VERSION 5.7 ;
  NOWIREEXTENSIONATPIN ON ;
  DIVIDERCHAR "/" ;
  BUSBITCHARS "[]" ;
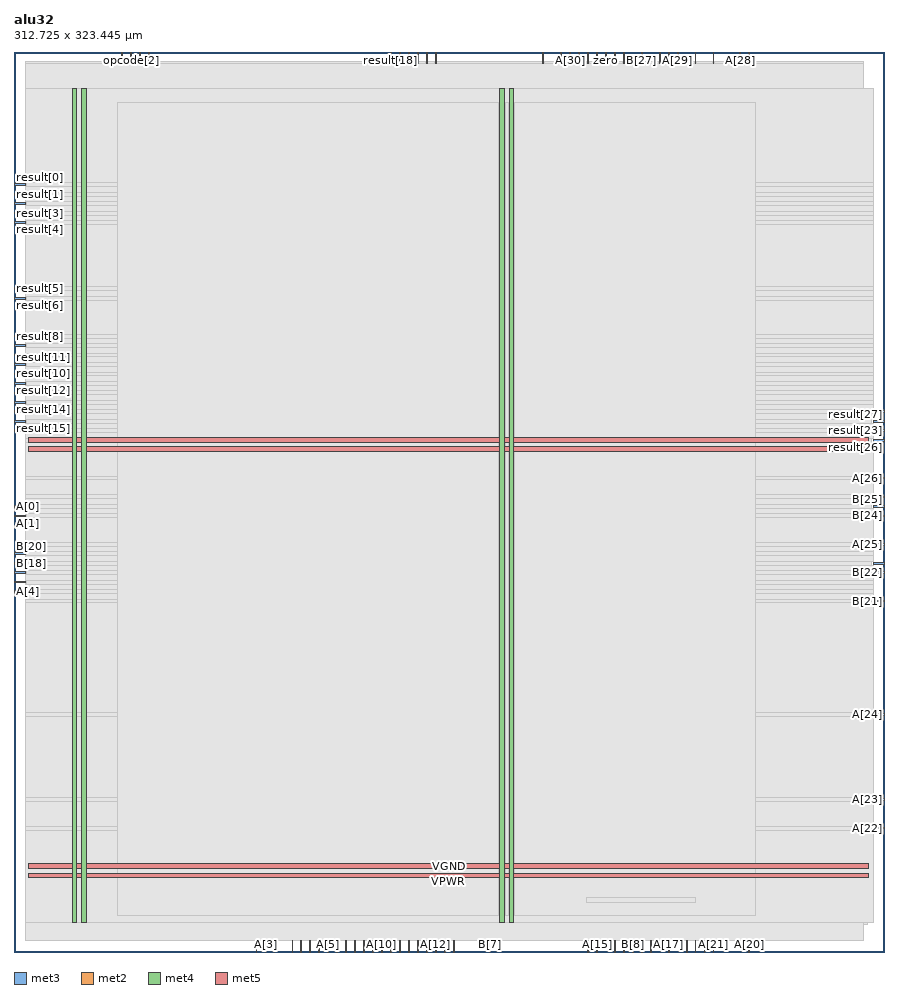
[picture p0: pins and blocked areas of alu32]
MACRO alu32
  CLASS BLOCK ;
  FOREIGN alu32 ;
  ORIGIN 0.000 0.000 ;
  SIZE 312.725 BY 323.445 ;
  PIN A[0]
    DIRECTION INPUT ;
    USE SIGNAL ;
    ANTENNAGATEAREA 0.196500 ;
    PORT
      LAYER met3 ;
        RECT 0.000 159.840 4.000 160.440 ;
    END
  END A[0]
  PIN A[10]
    DIRECTION INPUT ;
    USE SIGNAL ;
    ANTENNAGATEAREA 0.196500 ;
    PORT
      LAYER met2 ;
        RECT 132.110 0.000 132.390 4.000 ;
    END
  END A[10]
  PIN A[11]
    DIRECTION INPUT ;
    USE SIGNAL ;
    ANTENNAGATEAREA 0.372000 ;
    PORT
      LAYER met2 ;
        RECT 125.670 0.000 125.950 4.000 ;
    END
  END A[11]
  PIN A[12]
    DIRECTION INPUT ;
    USE SIGNAL ;
    ANTENNAGATEAREA 0.213000 ;
    PORT
      LAYER met2 ;
        RECT 151.430 0.000 151.710 4.000 ;
    END
  END A[12]
  PIN A[13]
    DIRECTION INPUT ;
    USE SIGNAL ;
    ANTENNAGATEAREA 0.213000 ;
    PORT
      LAYER met2 ;
        RECT 138.550 0.000 138.830 4.000 ;
    END
  END A[13]
  PIN A[14]
    DIRECTION INPUT ;
    USE SIGNAL ;
    ANTENNAGATEAREA 0.159000 ;
    PORT
      LAYER met2 ;
        RECT 144.990 0.000 145.270 4.000 ;
    END
  END A[14]
  PIN A[15]
    DIRECTION INPUT ;
    USE SIGNAL ;
    ANTENNAGATEAREA 0.213000 ;
    PORT
      LAYER met2 ;
        RECT 209.390 0.000 209.670 4.000 ;
    END
  END A[15]
  PIN A[16]
    DIRECTION INPUT ;
    USE SIGNAL ;
    ANTENNAGATEAREA 0.247500 ;
    PORT
      LAYER met2 ;
        RECT 215.830 0.000 216.110 4.000 ;
    END
  END A[16]
  PIN A[17]
    DIRECTION INPUT ;
    USE SIGNAL ;
    ANTENNAGATEAREA 0.495000 ;
    PORT
      LAYER met2 ;
        RECT 235.150 0.000 235.430 4.000 ;
    END
  END A[17]
  PIN A[18]
    DIRECTION INPUT ;
    USE SIGNAL ;
    ANTENNAGATEAREA 0.213000 ;
    PORT
      LAYER met2 ;
        RECT 206.170 0.000 206.450 4.000 ;
    END
  END A[18]
  PIN A[19]
    DIRECTION INPUT ;
    USE SIGNAL ;
    ANTENNAGATEAREA 0.159000 ;
    PORT
      LAYER met2 ;
        RECT 225.490 0.000 225.770 4.000 ;
    END
  END A[19]
  PIN A[1]
    DIRECTION INPUT ;
    USE SIGNAL ;
    ANTENNAGATEAREA 0.213000 ;
    PORT
      LAYER met3 ;
        RECT 0.000 156.440 4.000 157.040 ;
    END
  END A[1]
  PIN A[20]
    DIRECTION INPUT ;
    USE SIGNAL ;
    ANTENNAGATEAREA 0.196500 ;
    PORT
      LAYER met2 ;
        RECT 264.130 0.000 264.410 4.000 ;
    END
  END A[20]
  PIN A[21]
    DIRECTION INPUT ;
    USE SIGNAL ;
    ANTENNAGATEAREA 0.196500 ;
    PORT
      LAYER met2 ;
        RECT 251.250 0.000 251.530 4.000 ;
    END
  END A[21]
  PIN A[22]
    DIRECTION INPUT ;
    USE SIGNAL ;
    ANTENNAGATEAREA 0.213000 ;
    PORT
      LAYER met3 ;
        RECT 308.725 44.240 312.725 44.840 ;
    END
  END A[22]
  PIN A[23]
    DIRECTION INPUT ;
    USE SIGNAL ;
    ANTENNAGATEAREA 0.159000 ;
    PORT
      LAYER met3 ;
        RECT 308.725 54.440 312.725 55.040 ;
    END
  END A[23]
  PIN A[24]
    DIRECTION INPUT ;
    USE SIGNAL ;
    ANTENNAGATEAREA 0.159000 ;
    PORT
      LAYER met3 ;
        RECT 308.725 85.040 312.725 85.640 ;
    END
  END A[24]
  PIN A[25]
    DIRECTION INPUT ;
    USE SIGNAL ;
    ANTENNAGATEAREA 0.196500 ;
    PORT
      LAYER met3 ;
        RECT 308.725 146.240 312.725 146.840 ;
    END
  END A[25]
  PIN A[26]
    DIRECTION INPUT ;
    USE SIGNAL ;
    ANTENNAGATEAREA 0.213000 ;
    PORT
      LAYER met3 ;
        RECT 308.725 170.040 312.725 170.640 ;
    END
  END A[26]
  PIN A[27]
    DIRECTION INPUT ;
    USE SIGNAL ;
    ANTENNAGATEAREA 0.159000 ;
    PORT
      LAYER met2 ;
        RECT 264.130 319.445 264.410 323.445 ;
    END
  END A[27]
  PIN A[28]
    DIRECTION INPUT ;
    USE SIGNAL ;
    ANTENNAGATEAREA 0.213000 ;
    PORT
      LAYER met2 ;
        RECT 260.910 319.445 261.190 323.445 ;
    END
  END A[28]
  PIN A[29]
    DIRECTION INPUT ;
    USE SIGNAL ;
    ANTENNAGATEAREA 0.196500 ;
    PORT
      LAYER met2 ;
        RECT 238.370 319.445 238.650 323.445 ;
    END
  END A[29]
  PIN A[2]
    DIRECTION INPUT ;
    USE SIGNAL ;
    ANTENNAGATEAREA 0.196500 ;
    PORT
      LAYER met3 ;
        RECT 0.000 132.640 4.000 133.240 ;
    END
  END A[2]
  PIN A[30]
    DIRECTION INPUT ;
    USE SIGNAL ;
    ANTENNAGATEAREA 0.213000 ;
    PORT
      LAYER met2 ;
        RECT 199.730 319.445 200.010 323.445 ;
    END
  END A[30]
  PIN A[31]
    DIRECTION INPUT ;
    USE SIGNAL ;
    ANTENNAGATEAREA 0.159000 ;
    PORT
      LAYER met2 ;
        RECT 196.510 319.445 196.790 323.445 ;
    END
  END A[31]
  PIN A[3]
    DIRECTION INPUT ;
    USE SIGNAL ;
    ANTENNAGATEAREA 0.159000 ;
    PORT
      LAYER met2 ;
        RECT 90.250 0.000 90.530 4.000 ;
    END
  END A[3]
  PIN A[4]
    DIRECTION INPUT ;
    USE SIGNAL ;
    ANTENNAGATEAREA 0.213000 ;
    PORT
      LAYER met3 ;
        RECT 0.000 129.240 4.000 129.840 ;
    END
  END A[4]
  PIN A[5]
    DIRECTION INPUT ;
    USE SIGNAL ;
    ANTENNAGATEAREA 0.213000 ;
    PORT
      LAYER met2 ;
        RECT 112.790 0.000 113.070 4.000 ;
    END
  END A[5]
  PIN A[6]
    DIRECTION INPUT ;
    USE SIGNAL ;
    ANTENNAGATEAREA 0.159000 ;
    PORT
      LAYER met2 ;
        RECT 93.470 0.000 93.750 4.000 ;
    END
  END A[6]
  PIN A[7]
    DIRECTION INPUT ;
    USE SIGNAL ;
    ANTENNAGATEAREA 0.159000 ;
    PORT
      LAYER met2 ;
        RECT 87.030 0.000 87.310 4.000 ;
    END
  END A[7]
  PIN A[8]
    DIRECTION INPUT ;
    USE SIGNAL ;
    ANTENNAGATEAREA 0.213000 ;
    PORT
      LAYER met2 ;
        RECT 99.910 0.000 100.190 4.000 ;
    END
  END A[8]
  PIN A[9]
    DIRECTION INPUT ;
    USE SIGNAL ;
    ANTENNAGATEAREA 0.159000 ;
    PORT
      LAYER met2 ;
        RECT 128.890 0.000 129.170 4.000 ;
    END
  END A[9]
  PIN B[0]
    DIRECTION INPUT ;
    USE SIGNAL ;
    ANTENNAGATEAREA 0.213000 ;
    PORT
      LAYER met2 ;
        RECT 244.810 0.000 245.090 4.000 ;
    END
  END B[0]
  PIN B[10]
    DIRECTION INPUT ;
    USE SIGNAL ;
    ANTENNAGATEAREA 0.318000 ;
    PORT
      LAYER met2 ;
        RECT 148.210 0.000 148.490 4.000 ;
    END
  END B[10]
  PIN B[11]
    DIRECTION INPUT ;
    USE SIGNAL ;
    ANTENNAGATEAREA 0.196500 ;
    PORT
      LAYER met2 ;
        RECT 106.350 0.000 106.630 4.000 ;
    END
  END B[11]
  PIN B[12]
    DIRECTION INPUT ;
    USE SIGNAL ;
    ANTENNAGATEAREA 0.159000 ;
    PORT
      LAYER met2 ;
        RECT 135.330 0.000 135.610 4.000 ;
    END
  END B[12]
  PIN B[13]
    DIRECTION INPUT ;
    USE SIGNAL ;
    ANTENNAGATEAREA 0.196500 ;
    PORT
      LAYER met2 ;
        RECT 109.570 0.000 109.850 4.000 ;
    END
  END B[13]
  PIN B[14]
    DIRECTION INPUT ;
    USE SIGNAL ;
    ANTENNAGATEAREA 0.159000 ;
    PORT
      LAYER met2 ;
        RECT 103.130 0.000 103.410 4.000 ;
    END
  END B[14]
  PIN B[15]
    DIRECTION INPUT ;
    USE SIGNAL ;
    ANTENNAGATEAREA 0.159000 ;
    PORT
      LAYER met2 ;
        RECT 119.230 0.000 119.510 4.000 ;
    END
  END B[15]
  PIN B[16]
    DIRECTION INPUT ;
    USE SIGNAL ;
    ANTENNAGATEAREA 0.159000 ;
    PORT
      LAYER met2 ;
        RECT 116.010 0.000 116.290 4.000 ;
    END
  END B[16]
  PIN B[17]
    DIRECTION INPUT ;
    USE SIGNAL ;
    ANTENNAGATEAREA 0.196500 ;
    PORT
      LAYER met2 ;
        RECT 122.450 0.000 122.730 4.000 ;
    END
  END B[17]
  PIN B[18]
    DIRECTION INPUT ;
    USE SIGNAL ;
    ANTENNAGATEAREA 0.213000 ;
    PORT
      LAYER met3 ;
        RECT 0.000 139.440 4.000 140.040 ;
    END
  END B[18]
  PIN B[19]
    DIRECTION INPUT ;
    USE SIGNAL ;
    ANTENNAGATEAREA 0.213000 ;
    PORT
      LAYER met3 ;
        RECT 0.000 136.040 4.000 136.640 ;
    END
  END B[19]
  PIN B[1]
    DIRECTION INPUT ;
    USE SIGNAL ;
    ANTENNAGATEAREA 0.213000 ;
    PORT
      LAYER met2 ;
        RECT 241.590 0.000 241.870 4.000 ;
    END
  END B[1]
  PIN B[20]
    DIRECTION INPUT ;
    USE SIGNAL ;
    ANTENNAGATEAREA 0.126000 ;
    PORT
      LAYER met3 ;
        RECT 0.000 142.840 4.000 143.440 ;
    END
  END B[20]
  PIN B[21]
    DIRECTION INPUT ;
    USE SIGNAL ;
    ANTENNAGATEAREA 0.159000 ;
    PORT
      LAYER met3 ;
        RECT 308.725 125.840 312.725 126.440 ;
    END
  END B[21]
  PIN B[22]
    DIRECTION INPUT ;
    USE SIGNAL ;
    ANTENNAGATEAREA 0.213000 ;
    PORT
      LAYER met3 ;
        RECT 308.725 136.040 312.725 136.640 ;
    END
  END B[22]
  PIN B[23]
    DIRECTION INPUT ;
    USE SIGNAL ;
    ANTENNAGATEAREA 0.213000 ;
    PORT
      LAYER met3 ;
        RECT 308.725 139.440 312.725 140.040 ;
    END
  END B[23]
  PIN B[24]
    DIRECTION INPUT ;
    USE SIGNAL ;
    ANTENNAGATEAREA 0.159000 ;
    PORT
      LAYER met3 ;
        RECT 308.725 156.440 312.725 157.040 ;
    END
  END B[24]
  PIN B[25]
    DIRECTION INPUT ;
    USE SIGNAL ;
    ANTENNAGATEAREA 0.159000 ;
    PORT
      LAYER met3 ;
        RECT 308.725 159.840 312.725 160.440 ;
    END
  END B[25]
  PIN B[26]
    DIRECTION INPUT ;
    USE SIGNAL ;
    ANTENNAGATEAREA 0.196500 ;
    PORT
      LAYER met3 ;
        RECT 308.725 163.240 312.725 163.840 ;
    END
  END B[26]
  PIN B[27]
    DIRECTION INPUT ;
    USE SIGNAL ;
    ANTENNAGATEAREA 0.213000 ;
    PORT
      LAYER met2 ;
        RECT 225.490 319.445 225.770 323.445 ;
    END
  END B[27]
  PIN B[28]
    DIRECTION INPUT ;
    USE SIGNAL ;
    ANTENNAGATEAREA 0.213000 ;
    PORT
      LAYER met2 ;
        RECT 251.250 319.445 251.530 323.445 ;
    END
  END B[28]
  PIN B[29]
    DIRECTION INPUT ;
    USE SIGNAL ;
    ANTENNAGATEAREA 0.196500 ;
    PORT
      LAYER met2 ;
        RECT 235.150 319.445 235.430 323.445 ;
    END
  END B[29]
  PIN B[2]
    DIRECTION INPUT ;
    USE SIGNAL ;
    ANTENNAGATEAREA 1.842000 ;
    PORT
      LAYER met2 ;
        RECT 154.650 0.000 154.930 4.000 ;
    END
  END B[2]
  PIN B[30]
    DIRECTION INPUT ;
    USE SIGNAL ;
    ANTENNAGATEAREA 0.159000 ;
    PORT
      LAYER met2 ;
        RECT 244.810 319.445 245.090 323.445 ;
    END
  END B[30]
  PIN B[31]
    DIRECTION INPUT ;
    USE SIGNAL ;
    ANTENNAGATEAREA 0.126000 ;
    PORT
      LAYER met2 ;
        RECT 231.930 319.445 232.210 323.445 ;
    END
  END B[31]
  PIN B[3]
    DIRECTION INPUT ;
    USE SIGNAL ;
    ANTENNAGATEAREA 0.495000 ;
    PORT
      LAYER met2 ;
        RECT 219.050 0.000 219.330 4.000 ;
    END
  END B[3]
  PIN B[4]
    DIRECTION INPUT ;
    USE SIGNAL ;
    ANTENNAGATEAREA 0.213000 ;
    PORT
      LAYER met2 ;
        RECT 248.030 0.000 248.310 4.000 ;
    END
  END B[4]
  PIN B[5]
    DIRECTION INPUT ;
    USE SIGNAL ;
    ANTENNAGATEAREA 0.196500 ;
    PORT
      LAYER met2 ;
        RECT 228.710 0.000 228.990 4.000 ;
    END
  END B[5]
  PIN B[6]
    DIRECTION INPUT ;
    USE SIGNAL ;
    ANTENNAGATEAREA 0.159000 ;
    PORT
      LAYER met2 ;
        RECT 157.870 0.000 158.150 4.000 ;
    END
  END B[6]
  PIN B[7]
    DIRECTION INPUT ;
    USE SIGNAL ;
    ANTENNAGATEAREA 0.213000 ;
    PORT
      LAYER met2 ;
        RECT 170.750 0.000 171.030 4.000 ;
    END
  END B[7]
  PIN B[8]
    DIRECTION INPUT ;
    USE SIGNAL ;
    ANTENNAGATEAREA 0.196500 ;
    PORT
      LAYER met2 ;
        RECT 222.270 0.000 222.550 4.000 ;
    END
  END B[8]
  PIN B[9]
    DIRECTION INPUT ;
    USE SIGNAL ;
    ANTENNAGATEAREA 0.196500 ;
    PORT
      LAYER met2 ;
        RECT 141.770 0.000 142.050 4.000 ;
    END
  END B[9]
  PIN VGND
    DIRECTION INOUT ;
    USE GROUND ;
    PORT
      LAYER met4 ;
        RECT 24.340 10.640 25.940 310.320 ;
    END
    PORT
      LAYER met4 ;
        RECT 177.940 10.640 179.540 310.320 ;
    END
    PORT
      LAYER met5 ;
        RECT 5.280 30.030 307.060 31.630 ;
    END
    PORT
      LAYER met5 ;
        RECT 5.280 183.210 307.060 184.810 ;
    END
  END VGND
  PIN VPWR
    DIRECTION INOUT ;
    USE POWER ;
    PORT
      LAYER met4 ;
        RECT 21.040 10.640 22.640 310.320 ;
    END
    PORT
      LAYER met4 ;
        RECT 174.640 10.640 176.240 310.320 ;
    END
    PORT
      LAYER met5 ;
        RECT 5.280 26.730 307.060 28.330 ;
    END
    PORT
      LAYER met5 ;
        RECT 5.280 179.910 307.060 181.510 ;
    END
  END VPWR
  PIN carry
    DIRECTION OUTPUT ;
    USE SIGNAL ;
    ANTENNADIFFAREA 0.795200 ;
    PORT
      LAYER met2 ;
        RECT 209.390 319.445 209.670 323.445 ;
    END
  END carry
  PIN opcode[0]
    DIRECTION INPUT ;
    USE SIGNAL ;
    ANTENNAGATEAREA 0.159000 ;
    PORT
      LAYER met2 ;
        RECT 48.390 319.445 48.670 323.445 ;
    END
  END opcode[0]
  PIN opcode[1]
    DIRECTION INPUT ;
    USE SIGNAL ;
    ANTENNAGATEAREA 0.159000 ;
    PORT
      LAYER met2 ;
        RECT 38.730 319.445 39.010 323.445 ;
    END
  END opcode[1]
  PIN opcode[2]
    DIRECTION INPUT ;
    USE SIGNAL ;
    ANTENNAGATEAREA 0.213000 ;
    PORT
      LAYER met2 ;
        RECT 41.950 319.445 42.230 323.445 ;
    END
  END opcode[2]
  PIN opcode[3]
    DIRECTION INPUT ;
    USE SIGNAL ;
    ANTENNAGATEAREA 0.213000 ;
    PORT
      LAYER met2 ;
        RECT 45.170 319.445 45.450 323.445 ;
    END
  END opcode[3]
  PIN overflow
    DIRECTION OUTPUT ;
    USE SIGNAL ;
    ANTENNADIFFAREA 0.795200 ;
    PORT
      LAYER met2 ;
        RECT 219.050 319.445 219.330 323.445 ;
    END
  END overflow
  PIN result[0]
    DIRECTION OUTPUT ;
    USE SIGNAL ;
    ANTENNADIFFAREA 0.445500 ;
    PORT
      LAYER met3 ;
        RECT 0.000 275.440 4.000 276.040 ;
    END
  END result[0]
  PIN result[10]
    DIRECTION OUTPUT ;
    USE SIGNAL ;
    ANTENNADIFFAREA 0.445500 ;
    PORT
      LAYER met3 ;
        RECT 0.000 207.440 4.000 208.040 ;
    END
  END result[10]
  PIN result[11]
    DIRECTION OUTPUT ;
    USE SIGNAL ;
    ANTENNADIFFAREA 0.445500 ;
    PORT
      LAYER met3 ;
        RECT 0.000 210.840 4.000 211.440 ;
    END
  END result[11]
  PIN result[12]
    DIRECTION OUTPUT ;
    USE SIGNAL ;
    ANTENNADIFFAREA 0.445500 ;
    PORT
      LAYER met3 ;
        RECT 0.000 204.040 4.000 204.640 ;
    END
  END result[12]
  PIN result[13]
    DIRECTION OUTPUT ;
    USE SIGNAL ;
    ANTENNADIFFAREA 0.445500 ;
    PORT
      LAYER met3 ;
        RECT 0.000 200.640 4.000 201.240 ;
    END
  END result[13]
  PIN result[14]
    DIRECTION OUTPUT ;
    USE SIGNAL ;
    ANTENNADIFFAREA 0.445500 ;
    PORT
      LAYER met3 ;
        RECT 0.000 197.240 4.000 197.840 ;
    END
  END result[14]
  PIN result[15]
    DIRECTION OUTPUT ;
    USE SIGNAL ;
    ANTENNADIFFAREA 0.445500 ;
    PORT
      LAYER met3 ;
        RECT 0.000 190.440 4.000 191.040 ;
    END
  END result[15]
  PIN result[16]
    DIRECTION OUTPUT ;
    USE SIGNAL ;
    ANTENNADIFFAREA 0.445500 ;
    PORT
      LAYER met3 ;
        RECT 0.000 193.840 4.000 194.440 ;
    END
  END result[16]
  PIN result[17]
    DIRECTION OUTPUT ;
    USE SIGNAL ;
    ANTENNADIFFAREA 0.445500 ;
    PORT
      LAYER met3 ;
        RECT 0.000 187.040 4.000 187.640 ;
    END
  END result[17]
  PIN result[18]
    DIRECTION OUTPUT ;
    USE SIGNAL ;
    ANTENNADIFFAREA 0.795200 ;
    PORT
      LAYER met2 ;
        RECT 135.330 319.445 135.610 323.445 ;
    END
  END result[18]
  PIN result[19]
    DIRECTION OUTPUT ;
    USE SIGNAL ;
    ANTENNADIFFAREA 0.795200 ;
    PORT
      LAYER met2 ;
        RECT 144.990 319.445 145.270 323.445 ;
    END
  END result[19]
  PIN result[1]
    DIRECTION OUTPUT ;
    USE SIGNAL ;
    ANTENNADIFFAREA 0.445500 ;
    PORT
      LAYER met3 ;
        RECT 0.000 272.040 4.000 272.640 ;
    END
  END result[1]
  PIN result[20]
    DIRECTION OUTPUT ;
    USE SIGNAL ;
    ANTENNADIFFAREA 0.795200 ;
    PORT
      LAYER met2 ;
        RECT 138.550 319.445 138.830 323.445 ;
    END
  END result[20]
  PIN result[21]
    DIRECTION OUTPUT ;
    USE SIGNAL ;
    ANTENNADIFFAREA 0.795200 ;
    PORT
      LAYER met2 ;
        RECT 151.430 319.445 151.710 323.445 ;
    END
  END result[21]
  PIN result[22]
    DIRECTION OUTPUT ;
    USE SIGNAL ;
    ANTENNADIFFAREA 0.795200 ;
    PORT
      LAYER met2 ;
        RECT 148.210 319.445 148.490 323.445 ;
    END
  END result[22]
  PIN result[23]
    DIRECTION OUTPUT ;
    USE SIGNAL ;
    ANTENNADIFFAREA 0.445500 ;
    PORT
      LAYER met3 ;
        RECT 308.725 187.040 312.725 187.640 ;
    END
  END result[23]
  PIN result[24]
    DIRECTION OUTPUT ;
    USE SIGNAL ;
    ANTENNADIFFAREA 0.795200 ;
    PORT
      LAYER met2 ;
        RECT 141.770 319.445 142.050 323.445 ;
    END
  END result[24]
  PIN result[25]
    DIRECTION OUTPUT ;
    USE SIGNAL ;
    ANTENNADIFFAREA 0.795200 ;
    PORT
      LAYER met2 ;
        RECT 190.070 319.445 190.350 323.445 ;
    END
  END result[25]
  PIN result[26]
    DIRECTION OUTPUT ;
    USE SIGNAL ;
    ANTENNADIFFAREA 0.445500 ;
    PORT
      LAYER met3 ;
        RECT 308.725 183.640 312.725 184.240 ;
    END
  END result[26]
  PIN result[27]
    DIRECTION OUTPUT ;
    USE SIGNAL ;
    ANTENNADIFFAREA 0.445500 ;
    PORT
      LAYER met3 ;
        RECT 308.725 190.440 312.725 191.040 ;
    END
  END result[27]
  PIN result[28]
    DIRECTION OUTPUT ;
    USE SIGNAL ;
    ANTENNADIFFAREA 0.445500 ;
    PORT
      LAYER met3 ;
        RECT 308.725 193.840 312.725 194.440 ;
    END
  END result[28]
  PIN result[29]
    DIRECTION OUTPUT ;
    USE SIGNAL ;
    ANTENNADIFFAREA 0.795200 ;
    PORT
      LAYER met2 ;
        RECT 202.950 319.445 203.230 323.445 ;
    END
  END result[29]
  PIN result[2]
    DIRECTION OUTPUT ;
    USE SIGNAL ;
    ANTENNADIFFAREA 0.445500 ;
    PORT
      LAYER met3 ;
        RECT 0.000 268.640 4.000 269.240 ;
    END
  END result[2]
  PIN result[30]
    DIRECTION OUTPUT ;
    USE SIGNAL ;
    ANTENNADIFFAREA 0.795200 ;
    PORT
      LAYER met2 ;
        RECT 206.170 319.445 206.450 323.445 ;
    END
  END result[30]
  PIN result[31]
    DIRECTION OUTPUT ;
    USE SIGNAL ;
    ANTENNADIFFAREA 0.795200 ;
    PORT
      LAYER met2 ;
        RECT 215.830 319.445 216.110 323.445 ;
    END
  END result[31]
  PIN result[3]
    DIRECTION OUTPUT ;
    USE SIGNAL ;
    ANTENNADIFFAREA 0.445500 ;
    PORT
      LAYER met3 ;
        RECT 0.000 265.240 4.000 265.840 ;
    END
  END result[3]
  PIN result[4]
    DIRECTION OUTPUT ;
    USE SIGNAL ;
    ANTENNADIFFAREA 0.445500 ;
    PORT
      LAYER met3 ;
        RECT 0.000 261.840 4.000 262.440 ;
    END
  END result[4]
  PIN result[5]
    DIRECTION OUTPUT ;
    USE SIGNAL ;
    ANTENNADIFFAREA 0.445500 ;
    PORT
      LAYER met3 ;
        RECT 0.000 238.040 4.000 238.640 ;
    END
  END result[5]
  PIN result[6]
    DIRECTION OUTPUT ;
    USE SIGNAL ;
    ANTENNADIFFAREA 0.445500 ;
    PORT
      LAYER met3 ;
        RECT 0.000 234.640 4.000 235.240 ;
    END
  END result[6]
  PIN result[7]
    DIRECTION OUTPUT ;
    USE SIGNAL ;
    ANTENNADIFFAREA 0.445500 ;
    PORT
      LAYER met3 ;
        RECT 0.000 217.640 4.000 218.240 ;
    END
  END result[7]
  PIN result[8]
    DIRECTION OUTPUT ;
    USE SIGNAL ;
    ANTENNADIFFAREA 0.445500 ;
    PORT
      LAYER met3 ;
        RECT 0.000 221.040 4.000 221.640 ;
    END
  END result[8]
  PIN result[9]
    DIRECTION OUTPUT ;
    USE SIGNAL ;
    ANTENNADIFFAREA 0.445500 ;
    PORT
      LAYER met3 ;
        RECT 0.000 214.240 4.000 214.840 ;
    END
  END result[9]
  PIN zero
    DIRECTION OUTPUT ;
    USE SIGNAL ;
    ANTENNADIFFAREA 1.336500 ;
    PORT
      LAYER met2 ;
        RECT 212.610 319.445 212.890 323.445 ;
    END
  END zero
  OBS
      LAYER nwell ;
        RECT 5.330 10.795 307.010 310.165 ;
      LAYER li1 ;
        RECT 5.520 10.795 306.820 310.165 ;
      LAYER met1 ;
        RECT 4.210 9.900 306.820 310.320 ;
      LAYER met2 ;
        RECT 4.230 319.165 38.450 320.010 ;
        RECT 39.290 319.165 41.670 320.010 ;
        RECT 42.510 319.165 44.890 320.010 ;
        RECT 45.730 319.165 48.110 320.010 ;
        RECT 48.950 319.165 135.050 320.010 ;
        RECT 135.890 319.165 138.270 320.010 ;
        RECT 139.110 319.165 141.490 320.010 ;
        RECT 142.330 319.165 144.710 320.010 ;
        RECT 145.550 319.165 147.930 320.010 ;
        RECT 148.770 319.165 151.150 320.010 ;
        RECT 151.990 319.165 189.790 320.010 ;
        RECT 190.630 319.165 196.230 320.010 ;
        RECT 197.070 319.165 199.450 320.010 ;
        RECT 200.290 319.165 202.670 320.010 ;
        RECT 203.510 319.165 205.890 320.010 ;
        RECT 206.730 319.165 209.110 320.010 ;
        RECT 209.950 319.165 212.330 320.010 ;
        RECT 213.170 319.165 215.550 320.010 ;
        RECT 216.390 319.165 218.770 320.010 ;
        RECT 219.610 319.165 225.210 320.010 ;
        RECT 226.050 319.165 231.650 320.010 ;
        RECT 232.490 319.165 234.870 320.010 ;
        RECT 235.710 319.165 238.090 320.010 ;
        RECT 238.930 319.165 244.530 320.010 ;
        RECT 245.370 319.165 250.970 320.010 ;
        RECT 251.810 319.165 260.630 320.010 ;
        RECT 261.470 319.165 263.850 320.010 ;
        RECT 264.690 319.165 305.350 320.010 ;
        RECT 4.230 4.280 305.350 319.165 ;
        RECT 4.230 4.000 86.750 4.280 ;
        RECT 87.590 4.000 89.970 4.280 ;
        RECT 90.810 4.000 93.190 4.280 ;
        RECT 94.030 4.000 99.630 4.280 ;
        RECT 100.470 4.000 102.850 4.280 ;
        RECT 103.690 4.000 106.070 4.280 ;
        RECT 106.910 4.000 109.290 4.280 ;
        RECT 110.130 4.000 112.510 4.280 ;
        RECT 113.350 4.000 115.730 4.280 ;
        RECT 116.570 4.000 118.950 4.280 ;
        RECT 119.790 4.000 122.170 4.280 ;
        RECT 123.010 4.000 125.390 4.280 ;
        RECT 126.230 4.000 128.610 4.280 ;
        RECT 129.450 4.000 131.830 4.280 ;
        RECT 132.670 4.000 135.050 4.280 ;
        RECT 135.890 4.000 138.270 4.280 ;
        RECT 139.110 4.000 141.490 4.280 ;
        RECT 142.330 4.000 144.710 4.280 ;
        RECT 145.550 4.000 147.930 4.280 ;
        RECT 148.770 4.000 151.150 4.280 ;
        RECT 151.990 4.000 154.370 4.280 ;
        RECT 155.210 4.000 157.590 4.280 ;
        RECT 158.430 4.000 170.470 4.280 ;
        RECT 171.310 4.000 205.890 4.280 ;
        RECT 206.730 4.000 209.110 4.280 ;
        RECT 209.950 4.000 215.550 4.280 ;
        RECT 216.390 4.000 218.770 4.280 ;
        RECT 219.610 4.000 221.990 4.280 ;
        RECT 222.830 4.000 225.210 4.280 ;
        RECT 226.050 4.000 228.430 4.280 ;
        RECT 229.270 4.000 234.870 4.280 ;
        RECT 235.710 4.000 241.310 4.280 ;
        RECT 242.150 4.000 244.530 4.280 ;
        RECT 245.370 4.000 247.750 4.280 ;
        RECT 248.590 4.000 250.970 4.280 ;
        RECT 251.810 4.000 263.850 4.280 ;
        RECT 264.690 4.000 305.350 4.280 ;
      LAYER met3 ;
        RECT 3.990 276.440 308.725 310.245 ;
        RECT 4.400 275.040 308.725 276.440 ;
        RECT 3.990 273.040 308.725 275.040 ;
        RECT 4.400 271.640 308.725 273.040 ;
        RECT 3.990 269.640 308.725 271.640 ;
        RECT 4.400 268.240 308.725 269.640 ;
        RECT 3.990 266.240 308.725 268.240 ;
        RECT 4.400 264.840 308.725 266.240 ;
        RECT 3.990 262.840 308.725 264.840 ;
        RECT 4.400 261.440 308.725 262.840 ;
        RECT 3.990 239.040 308.725 261.440 ;
        RECT 4.400 237.640 308.725 239.040 ;
        RECT 3.990 235.640 308.725 237.640 ;
        RECT 4.400 234.240 308.725 235.640 ;
        RECT 3.990 222.040 308.725 234.240 ;
        RECT 4.400 220.640 308.725 222.040 ;
        RECT 3.990 218.640 308.725 220.640 ;
        RECT 4.400 217.240 308.725 218.640 ;
        RECT 3.990 215.240 308.725 217.240 ;
        RECT 4.400 213.840 308.725 215.240 ;
        RECT 3.990 211.840 308.725 213.840 ;
        RECT 4.400 210.440 308.725 211.840 ;
        RECT 3.990 208.440 308.725 210.440 ;
        RECT 4.400 207.040 308.725 208.440 ;
        RECT 3.990 205.040 308.725 207.040 ;
        RECT 4.400 203.640 308.725 205.040 ;
        RECT 3.990 201.640 308.725 203.640 ;
        RECT 4.400 200.240 308.725 201.640 ;
        RECT 3.990 198.240 308.725 200.240 ;
        RECT 4.400 196.840 308.725 198.240 ;
        RECT 3.990 194.840 308.725 196.840 ;
        RECT 4.400 193.440 308.325 194.840 ;
        RECT 3.990 191.440 308.725 193.440 ;
        RECT 4.400 190.040 308.325 191.440 ;
        RECT 3.990 188.040 308.725 190.040 ;
        RECT 4.400 186.640 308.325 188.040 ;
        RECT 3.990 184.640 308.725 186.640 ;
        RECT 3.990 183.240 308.325 184.640 ;
        RECT 3.990 171.040 308.725 183.240 ;
        RECT 3.990 169.640 308.325 171.040 ;
        RECT 3.990 164.240 308.725 169.640 ;
        RECT 3.990 162.840 308.325 164.240 ;
        RECT 3.990 160.840 308.725 162.840 ;
        RECT 4.400 159.440 308.325 160.840 ;
        RECT 3.990 157.440 308.725 159.440 ;
        RECT 4.400 156.040 308.325 157.440 ;
        RECT 3.990 147.240 308.725 156.040 ;
        RECT 3.990 145.840 308.325 147.240 ;
        RECT 3.990 143.840 308.725 145.840 ;
        RECT 4.400 142.440 308.725 143.840 ;
        RECT 3.990 140.440 308.725 142.440 ;
        RECT 4.400 139.040 308.325 140.440 ;
        RECT 3.990 137.040 308.725 139.040 ;
        RECT 4.400 135.640 308.325 137.040 ;
        RECT 3.990 133.640 308.725 135.640 ;
        RECT 4.400 132.240 308.725 133.640 ;
        RECT 3.990 130.240 308.725 132.240 ;
        RECT 4.400 128.840 308.725 130.240 ;
        RECT 3.990 126.840 308.725 128.840 ;
        RECT 3.990 125.440 308.325 126.840 ;
        RECT 3.990 86.040 308.725 125.440 ;
        RECT 3.990 84.640 308.325 86.040 ;
        RECT 3.990 55.440 308.725 84.640 ;
        RECT 3.990 54.040 308.325 55.440 ;
        RECT 3.990 45.240 308.725 54.040 ;
        RECT 3.990 43.840 308.325 45.240 ;
        RECT 3.990 10.715 308.725 43.840 ;
      LAYER met4 ;
        RECT 37.095 13.095 174.240 305.145 ;
        RECT 176.640 13.095 177.540 305.145 ;
        RECT 179.940 13.095 266.505 305.145 ;
      LAYER met5 ;
        RECT 205.740 17.900 245.060 19.500 ;
  END
END alu32
END LIBRARY

